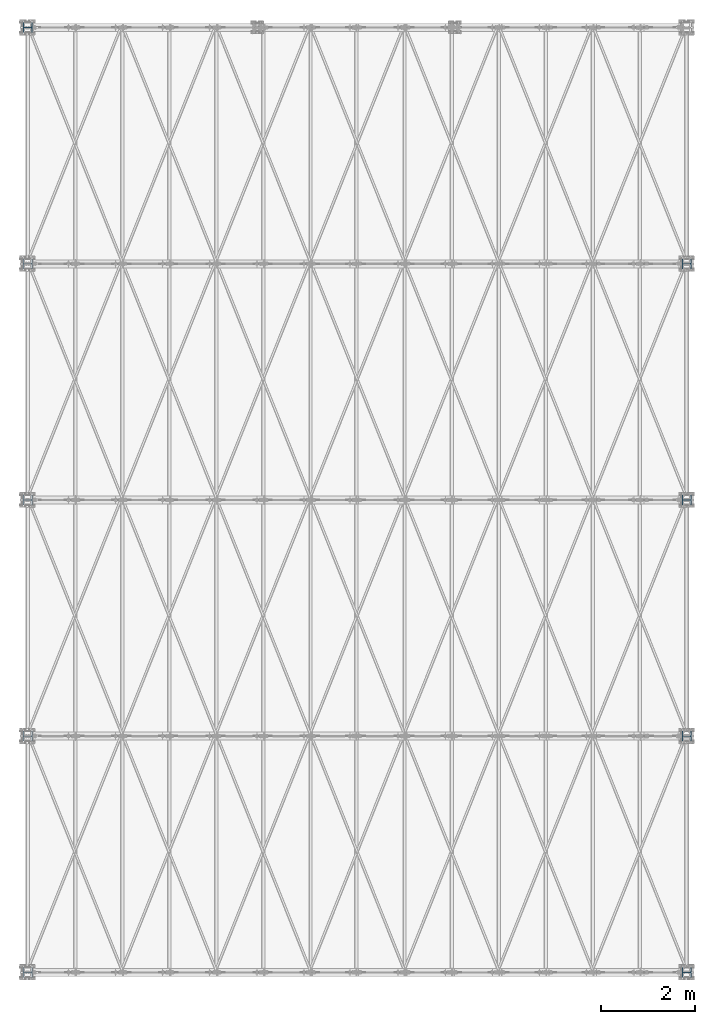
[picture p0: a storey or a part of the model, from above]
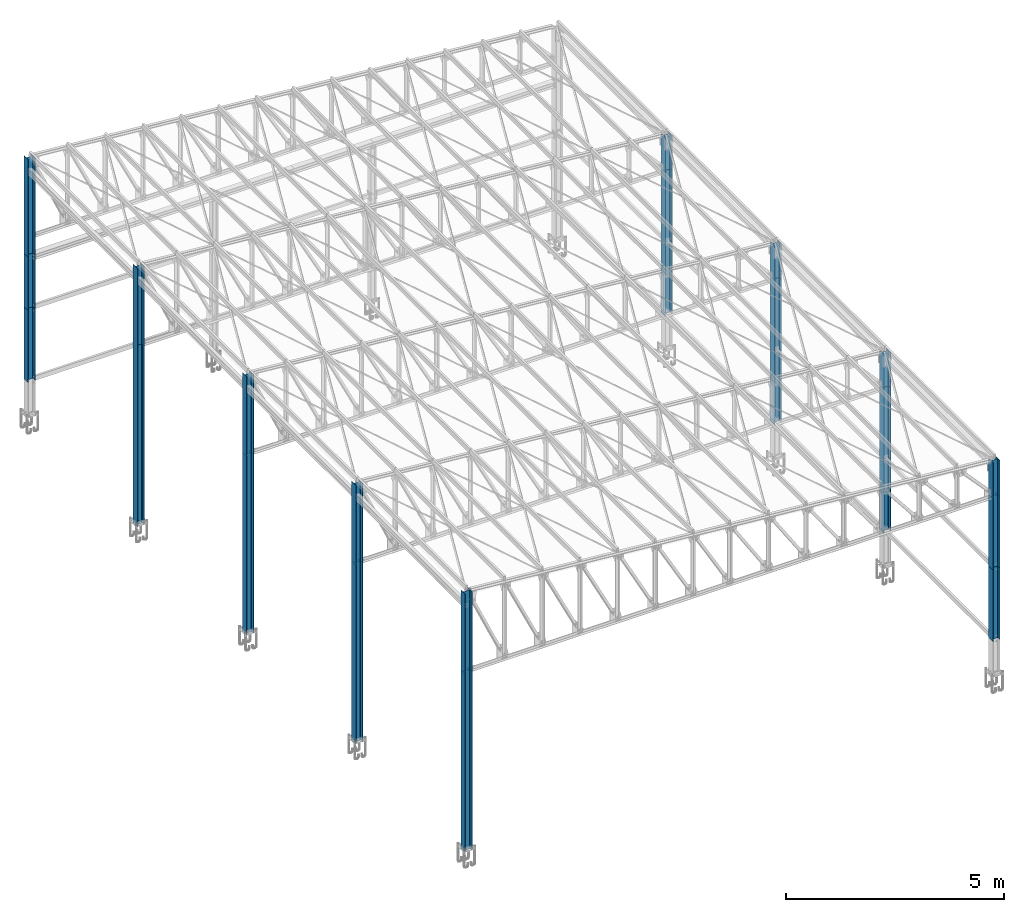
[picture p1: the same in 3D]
Properties of the parts of a building model (IFC4), part 1 of 2

# File
Description: ViewDefinition [CoordinationView]
Made in: IFC file generated by ModeSt (Tecnisoft s.a.s.)

# IfcBuildingStorey, Storey 0
In: Deposito
Elevation: 0 m

# IfcBeam: 12 HEA160 (6)
In: Storey 0
Type - PredefinedType: BEAM; Material: Acciaio
Description: 12 HEA160 - Acciaio
Pset_BeamCommon - LoadBearing: yes
BaseQuantities - ?: 0.003684 m2
Name | BaseQuantities, ? (m3) | BaseQuantities, ? (m)
70005 | 0.0103152 | 2.8
2 x 70005 | 0.0077364 | 2.1
2 x 70005 | 0.00768114 | 2.085
70005 | 0.0102415 | 2.78

# IfcBuildingElementProxy: 1 RHS120x60x8 (74)
In: Storey 0
Type - PredefinedType: MEMBER; Material: Acciaio
Description: 1 RHS120x60x8 - Acciaio
Pset_MemberCommon - LoadBearing: yes
BaseQuantities - ?: 0.002624 m2
Name | BaseQuantities, ? (m3) | BaseQuantities, ? (m)
4 x 210021 | 0.01312 | 5
4 x 230019 | 0.01312 | 5
4 x 190024 | 0.01312 | 5
4 x 170027 | 0.01312 | 5
4 x 150029 | 0.01312 | 5
4 x 130032 | 0.01312 | 5
4 x 110035 | 0.01312 | 5
4 x 90037 | 0.01312 | 5
4 x 220020 | 0.01312 | 5
4 x 200023 | 0.01312 | 5
4 x 180026 | 0.01312 | 5
4 x 160028 | 0.01312 | 5
4 x 140030 | 0.01312 | 5
4 x 120033 | 0.01312 | 5
4 x 100036 | 0.01312 | 5
4 x 280177 | 0.01312 | 5
4 x 280107 | 0.01312 | 5
280075 | 0.0128576 | 4.9
280075 | 0.0127658 | 4.865
280005 | 0.0127658 | 4.865
280005 | 0.0109814 | 4.185
280005 | 0.0128576 | 4.9
280075 | 0.0109814 | 4.185

# IfcBuildingElementProxy: 11 CONTROVENTI COPERTURA L50x5 (56)
In: Storey 0
Type - PredefinedType: MEMBER; Material: Acciaio
Description: 11 CONTROVENTI COPERTURA L50x5 - Acciaio
Pset_MemberCommon - LoadBearing: yes
BaseQuantities - ?: 0.000475 m2
Name | BaseQuantities, ? (m3) | BaseQuantities, ? (m)
4 x 210056 | 0.00255795 | 5.38516
4 x 210057 | 0.00255795 | 5.38516
250046 | 0.00255853 | 5.38638
3 x 230047 | 0.00255795 | 5.38516
3 x 230049 | 0.00255795 | 5.38516
4 x 190055 | 0.00255795 | 5.38516
4 x 190050 | 0.00255795 | 5.38516
3 x 150045 | 0.00255795 | 5.38516
4 x 170048 | 0.00255795 | 5.38516
4 x 170052 | 0.00255795 | 5.38516
2 x 130044 | 0.00255795 | 5.38516
3 x 150058 | 0.00255795 | 5.38516
110038 | 0.00255795 | 5.38516
2 x 250054 | 0.00255795 | 5.38516
250043 | 0.00255853 | 5.38638
250046 | 0.00255795 | 5.38516
230047 | 0.00255853 | 5.38638
230053 | 0.00255853 | 5.38638
2 x 130059 | 0.00255795 | 5.38516
2 x 230053 | 0.00255795 | 5.38516
250054 | 0.00255853 | 5.38638
230051 | 0.00255853 | 5.38638
110061 | 0.00255795 | 5.38516
230051 | 0.00255795 | 5.38516
230049 | 0.00255853 | 5.38638
250060 | 0.00255853 | 5.38638

# IfcBuildingElementProxy: 5 2L80x8 (330)
In: Storey 0
Type - PredefinedType: MEMBER; Material: Acciaio
Description: 5 2L80x8 - Acciaio
Pset_MemberCommon - LoadBearing: yes
BaseQuantities - ?: 0.003232 m2
Name | BaseQuantities, ? (m3) | BaseQuantities, ? (m)
4 x 230071 | 0.003232 | 1
2 x 100001 | 0.00476576 | 1.47455
2 x 13 | 0.00351369 | 1.08716
2 x 80001 | 0.0032197 | 0.996195
2 x 110001 | 0.00497708 | 1.53994
2 x 12 | 0.00379538 | 1.17431
2 x 120001 | 0.00519509 | 1.60739
2 x 11 | 0.00407706 | 1.26147
2 x 130001 | 0.00541896 | 1.67666
2 x 10 | 0.00435875 | 1.34862
2 x 140001 | 0.00564802 | 1.74753
2 x 9 | 0.00464044 | 1.43578
2 x 150001 | 0.00588165 | 1.81982
2 x 230071 | 0.00331777 | 1.02654
2 x 8 | 0.00492212 | 1.52293
2 x 160001 | 0.00616506 | 1.90751
2 x 230071 | 0.00314625 | 0.973467
2 x 7 | 0.00520381 | 1.61009
2 x 170001 | 0.00631745 | 1.95466
2 x 6 | 0.0054855 | 1.69725
2 x 180001 | 0.00660507 | 2.04365
2 x 5 | 0.00576719 | 1.7844
2 x 190001 | 0.0068524 | 2.12017
2 x 4 | 0.00604887 | 1.87156
2 x 200001 | 0.00710229 | 2.19749
2 x 3 | 0.00633056 | 1.95871
2 x 210001 | 0.00735447 | 2.27552
2 x 2 | 0.00661225 | 2.04587
2 x 230071 | 0.00324254 | 1.00326
2 x 220001 | 0.00760873 | 2.35419
2 x 1 | 0.00689394 | 2.13302
2 x 230001 | 0.0078692 | 2.43478
4 x 230072 | 0.003232 | 1
2 x 100002 | 0.00476576 | 1.47455
2 x 31 | 0.00351369 | 1.08716
2 x 80002 | 0.0032197 | 0.996195
2 x 110002 | 0.00497708 | 1.53994
2 x 30 | 0.00379538 | 1.17431
2 x 120002 | 0.00519509 | 1.60739
2 x 29 | 0.00407706 | 1.26147
2 x 130002 | 0.00541896 | 1.67666
2 x 28 | 0.00435875 | 1.34862
2 x 140002 | 0.00564802 | 1.74753
2 x 27 | 0.00464044 | 1.43578
2 x 150002 | 0.00588165 | 1.81982
2 x 230072 | 0.00331777 | 1.02654
2 x 26 | 0.00492212 | 1.52293
2 x 160002 | 0.00616506 | 1.90751
2 x 230072 | 0.00314625 | 0.973467
2 x 25 | 0.00520381 | 1.61009
2 x 170002 | 0.00631745 | 1.95466
2 x 24 | 0.0054855 | 1.69725
2 x 180002 | 0.00660507 | 2.04365
2 x 23 | 0.00576719 | 1.7844
2 x 190002 | 0.0068524 | 2.12017
2 x 22 | 0.00604887 | 1.87156
2 x 200002 | 0.00710229 | 2.19749
2 x 21 | 0.00633056 | 1.95871
2 x 210002 | 0.00735447 | 2.27552
2 x 20 | 0.00661225 | 2.04587
2 x 230072 | 0.00324254 | 1.00326
2 x 220002 | 0.00760873 | 2.35419
2 x 19 | 0.00689394 | 2.13302
2 x 230002 | 0.0078692 | 2.43478
4 x 230073 | 0.003232 | 1
2 x 100003 | 0.00476576 | 1.47455
2 x 46 | 0.00351369 | 1.08716
2 x 80003 | 0.0032197 | 0.996195
2 x 110003 | 0.00497708 | 1.53994
2 x 45 | 0.00379538 | 1.17431
2 x 120003 | 0.00519509 | 1.60739
2 x 44 | 0.00407706 | 1.26147
2 x 130003 | 0.00541896 | 1.67666
2 x 43 | 0.00435875 | 1.34862
2 x 140003 | 0.00564802 | 1.74753
2 x 42 | 0.00464044 | 1.43578
2 x 150003 | 0.00588165 | 1.81982
2 x 230073 | 0.00331777 | 1.02654
2 x 41 | 0.00492212 | 1.52293
2 x 160003 | 0.00616506 | 1.90751
2 x 230073 | 0.00314625 | 0.973467
2 x 40 | 0.00520381 | 1.61009
2 x 170003 | 0.00631745 | 1.95466
2 x 39 | 0.0054855 | 1.69725
2 x 180003 | 0.00660507 | 2.04365
2 x 38 | 0.00576719 | 1.7844
2 x 190003 | 0.0068524 | 2.12017
2 x 37 | 0.00604887 | 1.87156
2 x 200003 | 0.00710229 | 2.19749
2 x 36 | 0.00633056 | 1.95871
2 x 210003 | 0.00735447 | 2.27552
2 x 35 | 0.00661225 | 2.04587
2 x 230073 | 0.00324254 | 1.00326
2 x 220003 | 0.00760873 | 2.35419
2 x 34 | 0.00689394 | 2.13302
2 x 230003 | 0.0078692 | 2.43478
4 x 230074 | 0.003232 | 1
2 x 100004 | 0.00476576 | 1.47455
2 x 61 | 0.00351369 | 1.08716
2 x 80004 | 0.0032197 | 0.996195
2 x 110004 | 0.00497708 | 1.53994
2 x 60 | 0.00379538 | 1.17431
2 x 120004 | 0.00519509 | 1.60739
2 x 59 | 0.00407706 | 1.26147
2 x 130004 | 0.00541896 | 1.67666
2 x 58 | 0.00435875 | 1.34862
2 x 140004 | 0.00564802 | 1.74753
2 x 57 | 0.00464044 | 1.43578
2 x 150004 | 0.00588165 | 1.81982
2 x 230074 | 0.00331777 | 1.02654
2 x 56 | 0.00492212 | 1.52293
2 x 160004 | 0.00616506 | 1.90751
2 x 230074 | 0.00314625 | 0.973467
2 x 55 | 0.00520381 | 1.61009
2 x 170004 | 0.00631745 | 1.95466
2 x 54 | 0.0054855 | 1.69725
2 x 180004 | 0.00660507 | 2.04365
2 x 53 | 0.00576719 | 1.7844
2 x 190004 | 0.0068524 | 2.12017
2 x 52 | 0.00604887 | 1.87156
2 x 200004 | 0.00710229 | 2.19749
2 x 51 | 0.00633056 | 1.95871
2 x 210004 | 0.00735447 | 2.27552
2 x 50 | 0.00661225 | 2.04587
2 x 230074 | 0.00324254 | 1.00326
2 x 220004 | 0.00760873 | 2.35419
2 x 49 | 0.00689394 | 2.13302
2 x 230004 | 0.0078692 | 2.43478
4 x 230075 | 0.003232 | 1
2 x 100005 | 0.00476576 | 1.47455
2 x 78 | 0.00351369 | 1.08716
2 x 80005 | 0.0032197 | 0.996195
2 x 110005 | 0.00497708 | 1.53994
2 x 77 | 0.00379538 | 1.17431
2 x 120005 | 0.00519509 | 1.60739
2 x 76 | 0.00407706 | 1.26147
2 x 130005 | 0.00541896 | 1.67666
2 x 75 | 0.00435875 | 1.34862
2 x 140005 | 0.00564802 | 1.74753
2 x 73 | 0.00464044 | 1.43578
2 x 150005 | 0.00588165 | 1.81982
2 x 230075 | 0.00331777 | 1.02654
2 x 72 | 0.00492212 | 1.52293
2 x 160005 | 0.00616506 | 1.90751
2 x 230075 | 0.00314625 | 0.973467
2 x 71 | 0.00520381 | 1.61009
2 x 170005 | 0.00631745 | 1.95466
2 x 70 | 0.0054855 | 1.69725
2 x 180005 | 0.00660507 | 2.04365
2 x 69 | 0.00576719 | 1.7844
2 x 190005 | 0.0068524 | 2.12017
2 x 67 | 0.00604887 | 1.87156
2 x 200005 | 0.00710229 | 2.19749
2 x 66 | 0.00633056 | 1.95871
2 x 210005 | 0.00735447 | 2.27552
2 x 65 | 0.00661225 | 2.04587
2 x 230075 | 0.00324254 | 1.00326
2 x 220005 | 0.00760873 | 2.35419
2 x 64 | 0.00689394 | 2.13302
2 x 230005 | 0.0078692 | 2.43478

# IfcBuildingElementProxy: 9 ARCARECCI IPE180 (8)
In: Storey 0
Type - PredefinedType: MEMBER; Material: Acciaio
Description: 9 ARCARECCI IPE180 - Acciaio
Pset_MemberCommon - LoadBearing: yes
BaseQuantities - ?: 0.0023252 m2; ?: 0.011626 m3; ?: 5 m
Name
4 x 280019
4 x 280037

# IfcColumn: 4 PILASTRO HEA160 (6)
In: Storey 0
Type - PredefinedType: COLUMN; Material: Acciaio
Description: 4 PILASTRO HEA160 - Acciaio
Pset_ColumnCommon - LoadBearing: yes
BaseQuantities - ?: 0.003684 m2
Name | BaseQuantities, ? (m3) | BaseQuantities, ? (m)
68 | 0.003684 | 1
74 | 0.005526 | 1.5
74 | 0.007368 | 2
74 | 0.003684 | 1
68 | 0.005526 | 1.5
68 | 0.007368 | 2

# IfcColumn: 7 PILASTRO HEA200 (34)
In: Storey 0
Type - PredefinedType: COLUMN; Material: Acciaio
Description: 7 PILASTRO HEA200 - Acciaio
Pset_ColumnCommon - LoadBearing: yes
BaseQuantities - ?: 0.00502 m2
Name | BaseQuantities, ? (m3) | BaseQuantities, ? (m)
14 | 0.001004 | 0.2
16 | 0.002008 | 0.4
32 | 0.001004 | 0.2
18 | 0.002008 | 0.4
47 | 0.001004 | 0.2
33 | 0.002008 | 0.4
62 | 0.001004 | 0.2
48 | 0.002008 | 0.4
79 | 0.001004 | 0.2
63 | 0.002008 | 0.4
48 | 0.0251 | 5
18 | 0.0251 | 5
33 | 0.0251 | 5
16 | 0.0251 | 5
32 | 0.00502 | 1
14 | 0.00502 | 1
47 | 0.00502 | 1
62 | 0.00502 | 1
79 | 0.00502 | 1
2 x 32 | 0.01004 | 2
2 x 14 | 0.01004 | 2
2 x 47 | 0.01004 | 2
2 x 62 | 0.01004 | 2
79 | 0.01004 | 2
63 | 0.00502 | 1
79 | 0.00251 | 0.5
63 | 0.01004 | 2
63 | 0.00251 | 0.5
79 | 0.00753 | 1.5
63 | 0.00753 | 1.5

# IfcFastener: Collegamenti -001_-002 -002_-001 -002_-003 -003_-002 -003_-004 -004_-003 -004_-008 -008_-004 -009_-010 -010_-009 -010_-011 -011_-010 -011_-012 -012_-011 -012_-016 -016_-012 (128)
In: Storey 0
Type - PredefinedType: WELD
Description: 11x11

# IfcFastener: Collegamenti -005_-006 -008_-007 -013_-014 -016_-015 (32)
In: Storey 0
Type - PredefinedType: WELD
Description: 11x11

# IfcFastener: Collegamenti -006_-005 -006_-007 -007_-006 -007_-008 -014_-013 -014_-015 -015_-014 -015_-016 (64)
In: Storey 0
Type - PredefinedType: WELD
Description: 11x11

# IfcFastener: Collegamenti -051_7075 -053_7076 (24)
In: Storey 0
Type - PredefinedType: WELD
Description: 8x8

# IfcFastener: Collegamenti -064_-065 -065_-064 -065_-066 -066_-065 -066_-067 -067_-066 -067_-068 -068_-067 (144)
In: Storey 0
Type - PredefinedType: WELD
Name | Description
128 x Collegamenti -064_-065 -065_-064 -065_-066 -066_-065 -066_-067 -067_-066 -067_-068 -068_-067 | 7x7
16 x Collegamenti -064_-065 -065_-064 -065_-066 -066_-065 -066_-067 -067_-066 -067_-068 -068_-067 | 10x10

# IfcFastener: Collegamenti 0014_-001 0016_-054 0018_-056 0032_-002 0033_-058 0047_-003 0048_-060 0062_-004 0063_-005 0079_-008 (160)
In: Storey 0
Type - PredefinedType: WELD
Name | Description
120 x Collegamenti 0014_-001 0016_-054 0018_-056 0032_-002 0033_-058 0047_-003 0048_-060 0062_-004 0063_-005 0079_-008 | 14x14
40 x Collegamenti 0014_-001 0016_-054 0018_-056 0032_-002 0033_-058 0047_-003 0048_-060 0062_-004 0063_-005 0079_-008 | 8x8

# IfcFastener: Collegamenti 0068_-006 0074_-007 (32)
In: Storey 0
Type - PredefinedType: WELD
Name | Description
24 x Collegamenti 0068_-006 0074_-007 | 12x12
8 x Collegamenti 0068_-006 0074_-007 | 8x8

# IfcFastener: Collegamenti 7068_-014 7074_-015 (24)
In: Storey 0
Type - PredefinedType: WELD
Description: 8x8

# IfcFastener: Collegamento -069_-070 (12)
In: Storey 0
Type - PredefinedType: WELD
Description: 7x7

# IfcFastener: Collegamento -070_-069 (12)
In: Storey 0
Type - PredefinedType: WELD
Description: 7x7

# IfcFastener: Collegamento -070_-071 (12)
In: Storey 0
Type - PredefinedType: WELD
Description: 7x7

# IfcFastener: Collegamento -071_-070 (12)
In: Storey 0
Type - PredefinedType: WELD
Description: 7x7

# IfcFastener: Collegamento -071_-072 (12)
In: Storey 0
Type - PredefinedType: WELD
Description: 7x7

# IfcFastener: Collegamento -072_-071 (12)
In: Storey 0
Type - PredefinedType: WELD
Description: 7x7

# IfcFastener: Collegamento -072_-073 (12)
In: Storey 0
Type - PredefinedType: WELD
Description: 7x7

# IfcFastener: Collegamento -073_-072 (12)
In: Storey 0
Type - PredefinedType: WELD
Description: 7x7

# IfcFastener: Reticolare 2 (8)
In: Storey 0
Type - PredefinedType: WELD
Description: 10x10

# IfcFastener: Reticolare 3 (8)
In: Storey 0
Type - PredefinedType: WELD
Description: 10x10

# IfcFastener: Reticolare 4 (8)
In: Storey 0
Type - PredefinedType: WELD
Description: 10x10

# IfcFastener: Reticolare 5 (8)
In: Storey 0
Type - PredefinedType: WELD
Description: 10x10

# IfcFastener: Reticolare 6 (8)
In: Storey 0
Type - PredefinedType: WELD
Description: 10x10

# IfcMechanicalFastener: Collegamenti -001_-002 -002_-001 -002_-003 -003_-002 -003_-004 -004_-003 -004_-008 -008_-004 -009_-010 -010_-009 -010_-011 -011_-010 -011_-012 -012_-011 -012_-016 -016_-012 (256)
In: Storey 0
Type - PredefinedType: BOLT
Name | Description | NominalDiameter (m)
64 x Collegamenti -001_-002 -002_-001 -002_-003 -003_-002 -003_-004 -004_-003 -004_-008 -008_-004 -009_-010 -010_-009 -010_-011 -011_-010 -011_-012 -012_-011 -012_-016 -016_-012 | M12 | 0.0119993
64 x Collegamenti -001_-002 -002_-001 -002_-003 -003_-002 -003_-004 -004_-003 -004_-008 -008_-004 -009_-010 -010_-009 -010_-011 -011_-010 -011_-012 -012_-011 -012_-016 -016_-012 | M12 | 0.012
64 x Collegamenti -001_-002 -002_-001 -002_-003 -003_-002 -003_-004 -004_-003 -004_-008 -008_-004 -009_-010 -010_-009 -010_-011 -011_-010 -011_-012 -012_-011 -012_-016 -016_-012 | M24 | 0.024
64 x Collegamenti -001_-002 -002_-001 -002_-003 -003_-002 -003_-004 -004_-003 -004_-008 -008_-004 -009_-010 -010_-009 -010_-011 -011_-010 -011_-012 -012_-011 -012_-016 -016_-012 | M12 | 0.0119992

# IfcMechanicalFastener: Collegamenti -005_-006 -008_-007 -013_-014 -016_-015 (64)
In: Storey 0
Type - PredefinedType: BOLT
Name | Description | NominalDiameter (m)
16 x Collegamenti -005_-006 -008_-007 -013_-014 -016_-015 | M12 | 0.0119993
16 x Collegamenti -005_-006 -008_-007 -013_-014 -016_-015 | M12 | 0.012
16 x Collegamenti -005_-006 -008_-007 -013_-014 -016_-015 | M24 | 0.024
16 x Collegamenti -005_-006 -008_-007 -013_-014 -016_-015 | M12 | 0.0119992

# IfcMechanicalFastener: Collegamenti -006_-005 -006_-007 -007_-006 -007_-008 -014_-013 -014_-015 -015_-014 -015_-016 (128)
In: Storey 0
Type - PredefinedType: BOLT
Name | Description | NominalDiameter (m)
32 x Collegamenti -006_-005 -006_-007 -007_-006 -007_-008 -014_-013 -014_-015 -015_-014 -015_-016 | M12 | 0.0119993
32 x Collegamenti -006_-005 -006_-007 -007_-006 -007_-008 -014_-013 -014_-015 -015_-014 -015_-016 | M12 | 0.012
32 x Collegamenti -006_-005 -006_-007 -007_-006 -007_-008 -014_-013 -014_-015 -015_-014 -015_-016 | M24 | 0.024
32 x Collegamenti -006_-005 -006_-007 -007_-006 -007_-008 -014_-013 -014_-015 -015_-014 -015_-016 | M12 | 0.0119992

# IfcMechanicalFastener: Collegamenti -051_7075 -053_7076 (64)
In: Storey 0
Type - PredefinedType: BOLT
Name | Description | NominalDiameter (m)
16 x Collegamenti -051_7075 -053_7076 | M12 | 0.0119992
16 x Collegamenti -051_7075 -053_7076 | M12 | 0.012
16 x Collegamenti -051_7075 -053_7076 | M24 | 0.024
16 x Collegamenti -051_7075 -053_7076 | M12 | 0.0119991

# IfcMechanicalFastener: Collegamenti -064_-065 -065_-064 -065_-066 -066_-065 -066_-067 -067_-066 -067_-068 -068_-067 (128)
In: Storey 0
Type - PredefinedType: BOLT
Name | Description | NominalDiameter (m)
64 x Collegamenti -064_-065 -065_-064 -065_-066 -066_-065 -066_-067 -067_-066 -067_-068 -068_-067 | M12 | 0.0119991
32 x Collegamenti -064_-065 -065_-064 -065_-066 -066_-065 -066_-067 -067_-066 -067_-068 -068_-067 | M12 | 0.012
32 x Collegamenti -064_-065 -065_-064 -065_-066 -066_-065 -066_-067 -067_-066 -067_-068 -068_-067 | M24 | 0.024

# IfcMechanicalFastener: Collegamenti 0014_-001 0016_-054 0018_-056 0032_-002 0033_-058 0047_-003 0048_-060 0062_-004 0063_-005 0079_-008 (200)
In: Storey 0
Type - PredefinedType: BOLT
Name | Description | NominalDiameter (m)
24 x Collegamenti 0014_-001 0016_-054 0018_-056 0032_-002 0033_-058 0047_-003 0048_-060 0062_-004 0063_-005 0079_-008 | M16 | 0.016
80 x Collegamenti 0014_-001 0016_-054 0018_-056 0032_-002 0033_-058 0047_-003 0048_-060 0062_-004 0063_-005 0079_-008 | M32 | 0.032
24 x Collegamenti 0014_-001 0016_-054 0018_-056 0032_-002 0033_-058 0047_-003 0048_-060 0062_-004 0063_-005 0079_-008 | M16 | 0.0159998
48 x Collegamenti 0014_-001 0016_-054 0018_-056 0032_-002 0033_-058 0047_-003 0048_-060 0062_-004 0063_-005 0079_-008 | M16 | 0.0160001
24 x Collegamenti 0014_-001 0016_-054 0018_-056 0032_-002 0033_-058 0047_-003 0048_-060 0062_-004 0063_-005 0079_-008 | M16 | 0.0159988

# IfcMechanicalFastener: Collegamenti 0068_-006 0074_-007 (40)
In: Storey 0
Type - PredefinedType: BOLT
Name | Description | NominalDiameter (m)
24 x Collegamenti 0068_-006 0074_-007 | M12 | 0.0119992
16 x Collegamenti 0068_-006 0074_-007 | M24 | 0.024

# IfcMechanicalFastener: Collegamenti 7068_-014 7074_-015 (32)
In: Storey 0
Type - PredefinedType: BOLT
Name | Description | NominalDiameter (m)
16 x Collegamenti 7068_-014 7074_-015 | M12 | 0.0119991
8 x Collegamenti 7068_-014 7074_-015 | M12 | 0.012
8 x Collegamenti 7068_-014 7074_-015 | M24 | 0.024

# IfcMechanicalFastener: Collegamento -069_-070 (16)
In: Storey 0
Type - PredefinedType: BOLT
Name | Description | NominalDiameter (m)
8 x Collegamento -069_-070 | M12 | 0.0119999
4 x Collegamento -069_-070 | M12 | 0.012
4 x Collegamento -069_-070 | M24 | 0.024

# IfcMechanicalFastener: Collegamento -070_-069 (16)
In: Storey 0
Type - PredefinedType: BOLT
Name | Description | NominalDiameter (m)
8 x Collegamento -070_-069 | M12 | 0.0119999
4 x Collegamento -070_-069 | M12 | 0.012
4 x Collegamento -070_-069 | M24 | 0.024

# IfcMechanicalFastener: Collegamento -070_-071 (16)
In: Storey 0
Type - PredefinedType: BOLT
Name | Description | NominalDiameter (m)
8 x Collegamento -070_-071 | M12 | 0.0119999
4 x Collegamento -070_-071 | M12 | 0.012
4 x Collegamento -070_-071 | M24 | 0.024

# IfcMechanicalFastener: Collegamento -071_-070 (16)
In: Storey 0
Type - PredefinedType: BOLT
Name | Description | NominalDiameter (m)
8 x Collegamento -071_-070 | M12 | 0.0119999
4 x Collegamento -071_-070 | M12 | 0.012
4 x Collegamento -071_-070 | M24 | 0.024

# IfcMechanicalFastener: Collegamento -071_-072 (16)
In: Storey 0
Type - PredefinedType: BOLT
Name | Description | NominalDiameter (m)
8 x Collegamento -071_-072 | M12 | 0.0119999
4 x Collegamento -071_-072 | M12 | 0.012
4 x Collegamento -071_-072 | M24 | 0.024

# IfcMechanicalFastener: Collegamento -072_-071 (16)
In: Storey 0
Type - PredefinedType: BOLT
Name | Description | NominalDiameter (m)
8 x Collegamento -072_-071 | M12 | 0.0119999
4 x Collegamento -072_-071 | M12 | 0.012
4 x Collegamento -072_-071 | M24 | 0.024

# IfcMechanicalFastener: Collegamento -072_-073 (16)
In: Storey 0
Type - PredefinedType: BOLT
Name | Description | NominalDiameter (m)
8 x Collegamento -072_-073 | M12 | 0.0119999
4 x Collegamento -072_-073 | M12 | 0.012
4 x Collegamento -072_-073 | M24 | 0.024

# IfcMechanicalFastener: Collegamento -073_-072 (16)
In: Storey 0
Type - PredefinedType: BOLT
Name | Description | NominalDiameter (m)
8 x Collegamento -073_-072 | M12 | 0.0119999
4 x Collegamento -073_-072 | M12 | 0.012
4 x Collegamento -073_-072 | M24 | 0.024

# IfcMechanicalFastener: Reticolare 2 (880)
In: Storey 0
Type - PredefinedType: BOLT
Name | Description | NominalDiameter (m)
12 x Reticolare 2 | M12 | 0.0119991
172 x Reticolare 2 | M12 | 0.012
156 x Reticolare 2 | M24 | 0.024
8 x Reticolare 2 | M16 | 0.0159985
20 x Reticolare 2 | M16 | 0.016
20 x Reticolare 2 | M32 | 0.032
84 x Reticolare 2 | M12 | 0.0119999
50 x Reticolare 2 | M14 | 0.0139997
44 x Reticolare 2 | M14 | 0.014
44 x Reticolare 2 | M28 | 0.028
12 x Reticolare 2 | M14 | 0.0139998
42 x Reticolare 2 | M12 | 0.0119997
4 x Reticolare 2 | M14 | 0.0139994
4 x Reticolare 2 | M14 | 0.0139995
60 x Reticolare 2 | M12 | 0.0119996
16 x Reticolare 2 | M12 | 0.0119994
26 x Reticolare 2 | M16 | 0.0159997
4 x Reticolare 2 | M12 | 0.0119993
2 x Reticolare 2 | M12 | 0.0119998
2 x Reticolare 2 | M16 | 0.0159998
4 x Reticolare 2 | M16 | 0.0159988
24 x Reticolare 2 | M12 | 0.0120001
12 x Reticolare 2 | M12 | 0.0119989
10 x Reticolare 2 | M14 | 0.0139996
4 x Reticolare 2 | M14 | 0.013999
34 x Reticolare 2 | M12 | 0.011999
6 x Reticolare 2 | M12 | 0.0119995
4 x Reticolare 2 | M14 | 0.0140001

# IfcMechanicalFastener: Reticolare 3 (880)
In: Storey 0
Type - PredefinedType: BOLT
Name | Description | NominalDiameter (m)
52 x Reticolare 3 | M14 | 0.0139997
42 x Reticolare 3 | M14 | 0.014
42 x Reticolare 3 | M28 | 0.028
6 x Reticolare 3 | M18 | 0.0179991
4 x Reticolare 3 | M18 | 0.018
4 x Reticolare 3 | M36 | 0.036
76 x Reticolare 3 | M12 | 0.0119999
162 x Reticolare 3 | M12 | 0.012
146 x Reticolare 3 | M24 | 0.024
40 x Reticolare 3 | M16 | 0.016
28 x Reticolare 3 | M32 | 0.032
4 x Reticolare 3 | M16 | 0.0159996
40 x Reticolare 3 | M12 | 0.0119997
8 x Reticolare 3 | M14 | 0.0139998
4 x Reticolare 3 | M14 | 0.0139994
62 x Reticolare 3 | M12 | 0.0119996
16 x Reticolare 3 | M12 | 0.0119994
26 x Reticolare 3 | M16 | 0.0159997
4 x Reticolare 3 | M12 | 0.0119993
2 x Reticolare 3 | M12 | 0.0119998
2 x Reticolare 3 | M16 | 0.0159998
12 x Reticolare 3 | M16 | 0.0159988
16 x Reticolare 3 | M12 | 0.0120001
12 x Reticolare 3 | M12 | 0.0119989
8 x Reticolare 3 | M12 | 0.0119991
8 x Reticolare 3 | M14 | 0.0139989
4 x Reticolare 3 | M14 | 0.0139996
4 x Reticolare 3 | M14 | 0.013999
34 x Reticolare 3 | M12 | 0.011999
2 x Reticolare 3 | M18 | 0.017999
6 x Reticolare 3 | M12 | 0.0119995
4 x Reticolare 3 | M14 | 0.0140001

# IfcMechanicalFastener: Reticolare 4 (880)
In: Storey 0
Type - PredefinedType: BOLT
Name | Description | NominalDiameter (m)
44 x Reticolare 4 | M14 | 0.0139997
36 x Reticolare 4 | M14 | 0.014
36 x Reticolare 4 | M28 | 0.028
8 x Reticolare 4 | M16 | 0.0159985
40 x Reticolare 4 | M16 | 0.016
28 x Reticolare 4 | M32 | 0.032
84 x Reticolare 4 | M12 | 0.0119999
172 x Reticolare 4 | M12 | 0.012
156 x Reticolare 4 | M24 | 0.024
4 x Reticolare 4 | M16 | 0.0159996
48 x Reticolare 4 | M12 | 0.0119997
8 x Reticolare 4 | M14 | 0.0139998
4 x Reticolare 4 | M14 | 0.0139994
62 x Reticolare 4 | M12 | 0.0119996
16 x Reticolare 4 | M12 | 0.0119994
4 x Reticolare 4 | M12 | 0.0119993
18 x Reticolare 4 | M16 | 0.0159997
2 x Reticolare 4 | M12 | 0.0119998
2 x Reticolare 4 | M16 | 0.0159998
12 x Reticolare 4 | M16 | 0.0159988
20 x Reticolare 4 | M12 | 0.0120001
12 x Reticolare 4 | M12 | 0.0119989
8 x Reticolare 4 | M12 | 0.0119991
4 x Reticolare 4 | M14 | 0.0139996
4 x Reticolare 4 | M14 | 0.013999
34 x Reticolare 4 | M12 | 0.011999
4 x Reticolare 4 | M14 | 0.0139989
6 x Reticolare 4 | M12 | 0.0119995
4 x Reticolare 4 | M14 | 0.0140001

# IfcMechanicalFastener: Reticolare 5 (880)
In: Storey 0
Type - PredefinedType: BOLT
Name | Description | NominalDiameter (m)
84 x Reticolare 5 | M14 | 0.0139997
54 x Reticolare 5 | M14 | 0.014
54 x Reticolare 5 | M28 | 0.028
8 x Reticolare 5 | M16 | 0.0159985
12 x Reticolare 5 | M16 | 0.016
8 x Reticolare 5 | M32 | 0.032
84 x Reticolare 5 | M12 | 0.0119999
174 x Reticolare 5 | M12 | 0.012
158 x Reticolare 5 | M24 | 0.024
4 x Reticolare 5 | M16 | 0.0159996
48 x Reticolare 5 | M12 | 0.0119997
8 x Reticolare 5 | M14 | 0.0139998
4 x Reticolare 5 | M14 | 0.0139994
62 x Reticolare 5 | M12 | 0.0119996
16 x Reticolare 5 | M12 | 0.0119994
4 x Reticolare 5 | M12 | 0.0119993
2 x Reticolare 5 | M12 | 0.0119998
24 x Reticolare 5 | M12 | 0.0120001
12 x Reticolare 5 | M12 | 0.0119989
8 x Reticolare 5 | M12 | 0.0119991
4 x Reticolare 5 | M14 | 0.0139996
4 x Reticolare 5 | M14 | 0.013999
34 x Reticolare 5 | M12 | 0.011999
6 x Reticolare 5 | M12 | 0.0119995
4 x Reticolare 5 | M14 | 0.0140001

# IfcMechanicalFastener: Reticolare 6 (880)
In: Storey 0
Type - PredefinedType: BOLT
Name | Description | NominalDiameter (m)
28 x Reticolare 6 | M12 | 0.0119991
184 x Reticolare 6 | M12 | 0.012
168 x Reticolare 6 | M24 | 0.024
8 x Reticolare 6 | M16 | 0.0159985
4 x Reticolare 6 | M16 | 0.016
4 x Reticolare 6 | M32 | 0.032
84 x Reticolare 6 | M12 | 0.0119999
58 x Reticolare 6 | M14 | 0.0139997
48 x Reticolare 6 | M14 | 0.014
48 x Reticolare 6 | M28 | 0.028
12 x Reticolare 6 | M14 | 0.0139998
50 x Reticolare 6 | M12 | 0.0119997
4 x Reticolare 6 | M14 | 0.0139994
4 x Reticolare 6 | M14 | 0.0139995
60 x Reticolare 6 | M12 | 0.0119996
16 x Reticolare 6 | M12 | 0.0119994
4 x Reticolare 6 | M12 | 0.0119993
2 x Reticolare 6 | M12 | 0.0119998
24 x Reticolare 6 | M12 | 0.0120001
12 x Reticolare 6 | M12 | 0.0119989
10 x Reticolare 6 | M14 | 0.0139996
4 x Reticolare 6 | M14 | 0.013999
34 x Reticolare 6 | M12 | 0.011999
6 x Reticolare 6 | M12 | 0.0119995
4 x Reticolare 6 | M14 | 0.0140001

# IfcPlate: Collegamenti -001_-002 -002_-001 -002_-003 -003_-002 -003_-004 -004_-003 -004_-008 -008_-004 -009_-010 -010_-009 -010_-011 -011_-010 -011_-012 -012_-011 -012_-016 -016_-012 (16)
In: Storey 0
Type - PredefinedType: SHEET

# IfcPlate: Collegamenti -005_-006 -008_-007 -013_-014 -016_-015 (4)
In: Storey 0
Type - PredefinedType: SHEET

# IfcPlate: Collegamenti -006_-005 -006_-007 -007_-006 -007_-008 -014_-013 -014_-015 -015_-014 -015_-016 (8)
In: Storey 0
Type - PredefinedType: SHEET

# IfcPlate: Collegamenti -051_7075 -053_7076 (2)
In: Storey 0
Type - PredefinedType: SHEET

# IfcPlate: Collegamenti -064_-065 -065_-064 -065_-066 -066_-065 -066_-067 -067_-066 -067_-068 -068_-067 (32)
In: Storey 0
Type - PredefinedType: SHEET

# IfcPlate: Collegamenti 0014_-001 0016_-054 0018_-056 0032_-002 0033_-058 0047_-003 0048_-060 0062_-004 0063_-005 0079_-008 (90)
In: Storey 0
Type - PredefinedType: SHEET

# IfcPlate: Collegamenti 0068_-006 0074_-007 (18)
In: Storey 0
Type - PredefinedType: SHEET

# IfcPlate: Collegamenti 7068_-014 7074_-015 (2)
In: Storey 0
Type - PredefinedType: SHEET

# IfcPlate: Collegamento -069_-070
In: Storey 0
Type - PredefinedType: SHEET

# IfcPlate: Collegamento -070_-069
In: Storey 0
Type - PredefinedType: SHEET

# IfcPlate: Collegamento -070_-071
In: Storey 0
Type - PredefinedType: SHEET

# IfcPlate: Collegamento -071_-070
In: Storey 0
Type - PredefinedType: SHEET

# IfcPlate: Collegamento -071_-072
In: Storey 0
Type - PredefinedType: SHEET

# IfcPlate: Collegamento -072_-071
In: Storey 0
Type - PredefinedType: SHEET

# IfcPlate: Collegamento -072_-073
In: Storey 0
Type - PredefinedType: SHEET

# IfcPlate: Collegamento -073_-072
In: Storey 0
Type - PredefinedType: SHEET

# IfcPlate: Reticolare 2 (30)
In: Storey 0
Type - PredefinedType: SHEET

# IfcPlate: Reticolare 3 (30)
In: Storey 0
Type - PredefinedType: SHEET

# IfcPlate: Reticolare 4 (30)
In: Storey 0
Type - PredefinedType: SHEET

# IfcPlate: Reticolare 5 (30)
In: Storey 0
Type - PredefinedType: SHEET

# IfcPlate: Reticolare 6 (30)
In: Storey 0
Type - PredefinedType: SHEET

# IfcReinforcingBar (6)
In: Storey 0
Name | NominalDiameter (m) | CrossSectionArea (m2) | BarLength (m)
 | 0.016 | 0.00020106 | 0.469
 | 0.016 | 0.00020106 | 0.0187288
 | 0.016 | 0.00020106 | 0.0479995
 | 0.012 | 0.0001131 | 0.478
 | 0.012 | 0.0001131 | 0.0140467
 | 0.012 | 0.0001131 | 0.0359994

# IfcSlab: 1 Solaio copertura (56)
In: Storey 0
Type - PredefinedType: FLOOR; Material: Concrete
Description: 1 Solaio copertura - Altezza solaio 0.100000 - Spessore cappa 0.000000 -
Pset_SlabCommon - LoadBearing: yes
BaseQuantities - ?: 0.1 m
Name | BaseQuantities, ? (m2) | BaseQuantities, ? (m3)
1700 | -4.84779 | -0.484779
1800 | -4.98097 | -0.498097
1900 | -4.98097 | -0.498097
2000 | -4.98097 | -0.498097
2100 | -4.98097 | -0.498097
2200 | -4.98097 | -0.498097
2300 | -4.99734 | -0.499734
2301 | -4.99734 | -0.499734
2201 | -4.98097 | -0.498097
2101 | -4.98097 | -0.498097
2001 | -4.98097 | -0.498097
1901 | -4.98097 | -0.498097
1801 | -4.98097 | -0.498097
1701 | -4.84779 | -0.484779
1600 | -5.11416 | -0.511416
1500 | -4.98097 | -0.498097
1400 | -4.98097 | -0.498097
1300 | -4.98097 | -0.498097
1200 | -4.98097 | -0.498097
1100 | -4.98097 | -0.498097
1000 | -4.98097 | -0.498097
1001 | -4.98097 | -0.498097
1101 | -4.98097 | -0.498097
1201 | -4.98097 | -0.498097
1301 | -4.98097 | -0.498097
1401 | -4.98097 | -0.498097
1501 | -4.98097 | -0.498097
1601 | -5.11416 | -0.511416
1702 | -4.84779 | -0.484779
1802 | -4.98097 | -0.498097
1902 | -4.98097 | -0.498097
2002 | -4.98097 | -0.498097
2102 | -4.98097 | -0.498097
2202 | -4.98097 | -0.498097
2302 | -4.99734 | -0.499734
1602 | -5.11416 | -0.511416
1502 | -4.98097 | -0.498097
1402 | -4.98097 | -0.498097
1302 | -4.98097 | -0.498097
1202 | -4.98097 | -0.498097
1102 | -4.98097 | -0.498097
1002 | -4.98097 | -0.498097
2303 | -4.99734 | -0.499734
2203 | -4.98097 | -0.498097
2103 | -4.98097 | -0.498097
1903 | -4.98097 | -0.498097
1803 | -4.98097 | -0.498097
1703 | -4.84779 | -0.484779
1603 | -5.11416 | -0.511416
1503 | -4.98097 | -0.498097
1403 | -4.98097 | -0.498097
1203 | -4.98097 | -0.498097
1103 | -4.98097 | -0.498097
1003 | -4.98097 | -0.498097
1303 | -4.98097 | -0.498097
2003 | -4.98097 | -0.498097

# IfcReinforcingBarType, no part of this type: type
PredefinedType: MAIN; NominalDiameter: 0.016 m; CrossSectionArea: 0.00020106 m2; BarLength: 0.469 m; Material: Steel

# IfcReinforcingBarType, no part of this type: type
PredefinedType: MAIN; NominalDiameter: 0.016 m; CrossSectionArea: 0.00020106 m2; BarLength: 0.0187288 m; Material: Steel

# IfcReinforcingBarType, no part of this type: type
PredefinedType: MAIN; NominalDiameter: 0.016 m; CrossSectionArea: 0.00020106 m2; BarLength: 0.0479995 m; Material: Steel

# IfcReinforcingBarType, no part of this type: type
PredefinedType: MAIN; NominalDiameter: 0.012 m; CrossSectionArea: 0.0001131 m2; BarLength: 0.478 m; Material: Steel

# IfcReinforcingBarType, no part of this type: type
PredefinedType: MAIN; NominalDiameter: 0.012 m; CrossSectionArea: 0.0001131 m2; BarLength: 0.0140467 m; Material: Steel

# IfcReinforcingBarType, no part of this type: type
PredefinedType: MAIN; NominalDiameter: 0.012 m; CrossSectionArea: 0.0001131 m2; BarLength: 0.0359994 m; Material: Steel

# Material: Acciaio
Acciaio - Mass Density: 7850; Poisson Ratio: 0.3; Shear Modulus: 8000000000; Thermal Expansion Coefficient: 0.00001; Young Modulus: 20999999488

# Material: Acciaio
Acciaio - Mass Density: 7850; Poisson Ratio: 0.3; Shear Modulus: 8000000000; Thermal Expansion Coefficient: 0.00001; Young Modulus: 20999999488

# Material: Acciaio
Acciaio - Mass Density: 7850; Poisson Ratio: 0.3; Shear Modulus: 8000000000; Thermal Expansion Coefficient: 0.00001; Young Modulus: 20999999488

# Material: Acciaio
Acciaio - Mass Density: 7850; Poisson Ratio: 0.3; Shear Modulus: 8000000000; Thermal Expansion Coefficient: 0.00001; Young Modulus: 20999999488

# Material: Acciaio
Acciaio - Mass Density: 7850; Poisson Ratio: 0.3; Shear Modulus: 8000000000; Thermal Expansion Coefficient: 0.00001; Young Modulus: 20999999488

# Material: Acciaio
Acciaio - Mass Density: 7850; Poisson Ratio: 0.3; Shear Modulus: 8000000000; Thermal Expansion Coefficient: 0.00001; Young Modulus: 20999999488

# Material: Acciaio
Acciaio - Mass Density: 7850; Poisson Ratio: 0.3; Shear Modulus: 8000000000; Thermal Expansion Coefficient: 0.00001; Young Modulus: 20999999488

# Material: Acciaio
Acciaio - Mass Density: 7850; Poisson Ratio: 0.3; Shear Modulus: 8000000000; Thermal Expansion Coefficient: 0.00001; Young Modulus: 20999999488

# Material: Acciaio
Acciaio - Mass Density: 7850; Poisson Ratio: 0.3; Shear Modulus: 8000000000; Thermal Expansion Coefficient: 0.00001; Young Modulus: 20999999488

# Material: Acciaio
Acciaio - Mass Density: 7850; Poisson Ratio: 0.3; Shear Modulus: 8000000000; Thermal Expansion Coefficient: 0.00001; Young Modulus: 20999999488

# Material: Acciaio
Acciaio - Mass Density: 7850; Poisson Ratio: 0.3; Shear Modulus: 8000000000; Thermal Expansion Coefficient: 0.00001; Young Modulus: 20999999488

# Material: Acciaio
Acciaio - Mass Density: 7850; Poisson Ratio: 0.3; Shear Modulus: 8000000000; Thermal Expansion Coefficient: 0.00001; Young Modulus: 20999999488

# Material: Acciaio
Acciaio - Mass Density: 7850; Poisson Ratio: 0.3; Shear Modulus: 8000000000; Thermal Expansion Coefficient: 0.00001; Young Modulus: 20999999488

# Material: Acciaio
Acciaio - Mass Density: 7850; Poisson Ratio: 0.3; Shear Modulus: 8000000000; Thermal Expansion Coefficient: 0.00001; Young Modulus: 20999999488

# Material: Acciaio
Acciaio - Mass Density: 7850; Poisson Ratio: 0.3; Shear Modulus: 8000000000; Thermal Expansion Coefficient: 0.00001; Young Modulus: 20999999488

# Material: Acciaio
Acciaio - Mass Density: 7850; Poisson Ratio: 0.3; Shear Modulus: 8000000000; Thermal Expansion Coefficient: 0.00001; Young Modulus: 20999999488

# Material: Acciaio
Acciaio - Mass Density: 7850; Poisson Ratio: 0.3; Shear Modulus: 8000000000; Thermal Expansion Coefficient: 0.00001; Young Modulus: 20999999488

# Material: Acciaio
Acciaio - Mass Density: 7850; Poisson Ratio: 0.3; Shear Modulus: 8000000000; Thermal Expansion Coefficient: 0.00001; Young Modulus: 20999999488

# Material: Acciaio
Acciaio - Mass Density: 7850; Poisson Ratio: 0.3; Shear Modulus: 8000000000; Thermal Expansion Coefficient: 0.00001; Young Modulus: 20999999488

# Material: Acciaio
Acciaio - Mass Density: 7850; Poisson Ratio: 0.3; Shear Modulus: 8000000000; Thermal Expansion Coefficient: 0.00001; Young Modulus: 20999999488

# Material: Acciaio
Acciaio - Mass Density: 7850; Poisson Ratio: 0.3; Shear Modulus: 8000000000; Thermal Expansion Coefficient: 0.00001; Young Modulus: 20999999488

# Material: Acciaio
Acciaio - Mass Density: 7850; Poisson Ratio: 0.3; Shear Modulus: 8000000000; Thermal Expansion Coefficient: 0.00001; Young Modulus: 20999999488

# Material: Acciaio
Acciaio - Mass Density: 7850; Poisson Ratio: 0.3; Shear Modulus: 8000000000; Thermal Expansion Coefficient: 0.00001; Young Modulus: 20999999488

# Material: Acciaio
Acciaio - Mass Density: 7850; Poisson Ratio: 0.3; Shear Modulus: 8000000000; Thermal Expansion Coefficient: 0.00001; Young Modulus: 20999999488

# Material: Acciaio
Acciaio - Mass Density: 7850; Poisson Ratio: 0.3; Shear Modulus: 8000000000; Thermal Expansion Coefficient: 0.00001; Young Modulus: 20999999488

# Material: Acciaio
Acciaio - Mass Density: 7850; Poisson Ratio: 0.3; Shear Modulus: 8000000000; Thermal Expansion Coefficient: 0.00001; Young Modulus: 20999999488

# Material: Acciaio
Acciaio - Mass Density: 7850; Poisson Ratio: 0.3; Shear Modulus: 8000000000; Thermal Expansion Coefficient: 0.00001; Young Modulus: 20999999488

# Material: Acciaio
Acciaio - Mass Density: 7850; Poisson Ratio: 0.3; Shear Modulus: 8000000000; Thermal Expansion Coefficient: 0.00001; Young Modulus: 20999999488

# Material: Acciaio
Acciaio - Mass Density: 7850; Poisson Ratio: 0.3; Shear Modulus: 8000000000; Thermal Expansion Coefficient: 0.00001; Young Modulus: 20999999488

# Material: Acciaio
Acciaio - Mass Density: 7850; Poisson Ratio: 0.3; Shear Modulus: 8000000000; Thermal Expansion Coefficient: 0.00001; Young Modulus: 20999999488

# Material: Acciaio
Acciaio - Mass Density: 7850; Poisson Ratio: 0.3; Shear Modulus: 8000000000; Thermal Expansion Coefficient: 0.00001; Young Modulus: 20999999488

# Material: Acciaio
Acciaio - Mass Density: 7850; Poisson Ratio: 0.3; Shear Modulus: 8000000000; Thermal Expansion Coefficient: 0.00001; Young Modulus: 20999999488

# Material: Acciaio
Acciaio - Mass Density: 7850; Poisson Ratio: 0.3; Shear Modulus: 8000000000; Thermal Expansion Coefficient: 0.00001; Young Modulus: 20999999488

# Material: Acciaio
Acciaio - Mass Density: 7850; Poisson Ratio: 0.3; Shear Modulus: 8000000000; Thermal Expansion Coefficient: 0.00001; Young Modulus: 20999999488

# Material: Acciaio
Acciaio - Mass Density: 7850; Poisson Ratio: 0.3; Shear Modulus: 8000000000; Thermal Expansion Coefficient: 0.00001; Young Modulus: 20999999488

# Material: Acciaio
Acciaio - Mass Density: 7850; Poisson Ratio: 0.3; Shear Modulus: 8000000000; Thermal Expansion Coefficient: 0.00001; Young Modulus: 20999999488

# Material: Acciaio
Acciaio - Mass Density: 7850; Poisson Ratio: 0.3; Shear Modulus: 8000000000; Thermal Expansion Coefficient: 0.00001; Young Modulus: 20999999488

# Material: Acciaio
Acciaio - Mass Density: 7850; Poisson Ratio: 0.3; Shear Modulus: 8000000000; Thermal Expansion Coefficient: 0.00001; Young Modulus: 20999999488

# Material: Acciaio
Acciaio - Mass Density: 7850; Poisson Ratio: 0.3; Shear Modulus: 8000000000; Thermal Expansion Coefficient: 0.00001; Young Modulus: 20999999488

# Material: Acciaio
Acciaio - Mass Density: 7850; Poisson Ratio: 0.3; Shear Modulus: 8000000000; Thermal Expansion Coefficient: 0.00001; Young Modulus: 20999999488

# Material: Acciaio
Acciaio - Mass Density: 7850; Poisson Ratio: 0.3; Shear Modulus: 8000000000; Thermal Expansion Coefficient: 0.00001; Young Modulus: 20999999488

# Material: Acciaio
Acciaio - Mass Density: 7850; Poisson Ratio: 0.3; Shear Modulus: 8000000000; Thermal Expansion Coefficient: 0.00001; Young Modulus: 20999999488

# Material: Acciaio
Acciaio - Mass Density: 7850; Poisson Ratio: 0.3; Shear Modulus: 8000000000; Thermal Expansion Coefficient: 0.00001; Young Modulus: 20999999488

# Material: Acciaio
Acciaio - Mass Density: 7850; Poisson Ratio: 0.3; Shear Modulus: 8000000000; Thermal Expansion Coefficient: 0.00001; Young Modulus: 20999999488

# Material: Acciaio
Acciaio - Mass Density: 7850; Poisson Ratio: 0.3; Shear Modulus: 8000000000; Thermal Expansion Coefficient: 0.00001; Young Modulus: 20999999488

# Material: Acciaio
Acciaio - Mass Density: 7850; Poisson Ratio: 0.3; Shear Modulus: 8000000000; Thermal Expansion Coefficient: 0.00001; Young Modulus: 20999999488

# Material: Acciaio
Acciaio - Mass Density: 7850; Poisson Ratio: 0.3; Shear Modulus: 8000000000; Thermal Expansion Coefficient: 0.00001; Young Modulus: 20999999488

# Material: Acciaio
Acciaio - Mass Density: 7850; Poisson Ratio: 0.3; Shear Modulus: 8000000000; Thermal Expansion Coefficient: 0.00001; Young Modulus: 20999999488

# Material: Acciaio
Acciaio - Mass Density: 7850; Poisson Ratio: 0.3; Shear Modulus: 8000000000; Thermal Expansion Coefficient: 0.00001; Young Modulus: 20999999488

# Material: Acciaio
Acciaio - Mass Density: 7850; Poisson Ratio: 0.3; Shear Modulus: 8000000000; Thermal Expansion Coefficient: 0.00001; Young Modulus: 20999999488

# Material: Acciaio
Acciaio - Mass Density: 7850; Poisson Ratio: 0.3; Shear Modulus: 8000000000; Thermal Expansion Coefficient: 0.00001; Young Modulus: 20999999488

# Material: Acciaio
Acciaio - Mass Density: 7850; Poisson Ratio: 0.3; Shear Modulus: 8000000000; Thermal Expansion Coefficient: 0.00001; Young Modulus: 20999999488

# Material: Acciaio
Acciaio - Mass Density: 7850; Poisson Ratio: 0.3; Shear Modulus: 8000000000; Thermal Expansion Coefficient: 0.00001; Young Modulus: 20999999488

# Material: Acciaio
Acciaio - Mass Density: 7850; Poisson Ratio: 0.3; Shear Modulus: 8000000000; Thermal Expansion Coefficient: 0.00001; Young Modulus: 20999999488

# Material: Acciaio
Acciaio - Mass Density: 7850; Poisson Ratio: 0.3; Shear Modulus: 8000000000; Thermal Expansion Coefficient: 0.00001; Young Modulus: 20999999488

# Material: Acciaio
Acciaio - Mass Density: 7850; Poisson Ratio: 0.3; Shear Modulus: 8000000000; Thermal Expansion Coefficient: 0.00001; Young Modulus: 20999999488

# Material: Acciaio
Acciaio - Mass Density: 7850; Poisson Ratio: 0.3; Shear Modulus: 8000000000; Thermal Expansion Coefficient: 0.00001; Young Modulus: 20999999488

# Material: Acciaio
Acciaio - Mass Density: 7850; Poisson Ratio: 0.3; Shear Modulus: 8000000000; Thermal Expansion Coefficient: 0.00001; Young Modulus: 20999999488

# Material: Acciaio
Acciaio - Mass Density: 7850; Poisson Ratio: 0.3; Shear Modulus: 8000000000; Thermal Expansion Coefficient: 0.00001; Young Modulus: 20999999488

# Material: Acciaio
Acciaio - Mass Density: 7850; Poisson Ratio: 0.3; Shear Modulus: 8000000000; Thermal Expansion Coefficient: 0.00001; Young Modulus: 20999999488

# Material: Acciaio
Acciaio - Mass Density: 7850; Poisson Ratio: 0.3; Shear Modulus: 8000000000; Thermal Expansion Coefficient: 0.00001; Young Modulus: 20999999488

# Material: Acciaio
Acciaio - Mass Density: 7850; Poisson Ratio: 0.3; Shear Modulus: 8000000000; Thermal Expansion Coefficient: 0.00001; Young Modulus: 20999999488

# Material: Acciaio
Acciaio - Mass Density: 7850; Poisson Ratio: 0.3; Shear Modulus: 8000000000; Thermal Expansion Coefficient: 0.00001; Young Modulus: 20999999488

# Material: Acciaio
Acciaio - Mass Density: 7850; Poisson Ratio: 0.3; Shear Modulus: 8000000000; Thermal Expansion Coefficient: 0.00001; Young Modulus: 20999999488

# Material: Acciaio
Acciaio - Mass Density: 7850; Poisson Ratio: 0.3; Shear Modulus: 8000000000; Thermal Expansion Coefficient: 0.00001; Young Modulus: 20999999488

# Material: Acciaio
Acciaio - Mass Density: 7850; Poisson Ratio: 0.3; Shear Modulus: 8000000000; Thermal Expansion Coefficient: 0.00001; Young Modulus: 20999999488

# Material: Acciaio
Acciaio - Mass Density: 7850; Poisson Ratio: 0.3; Shear Modulus: 8000000000; Thermal Expansion Coefficient: 0.00001; Young Modulus: 20999999488

# Material: Acciaio
Acciaio - Mass Density: 7850; Poisson Ratio: 0.3; Shear Modulus: 8000000000; Thermal Expansion Coefficient: 0.00001; Young Modulus: 20999999488

# Material: Acciaio
Acciaio - Mass Density: 7850; Poisson Ratio: 0.3; Shear Modulus: 8000000000; Thermal Expansion Coefficient: 0.00001; Young Modulus: 20999999488

# Material: Acciaio
Acciaio - Mass Density: 7850; Poisson Ratio: 0.3; Shear Modulus: 8000000000; Thermal Expansion Coefficient: 0.00001; Young Modulus: 20999999488

# Material: Acciaio
Acciaio - Mass Density: 7850; Poisson Ratio: 0.3; Shear Modulus: 8000000000; Thermal Expansion Coefficient: 0.00001; Young Modulus: 20999999488

# Material: Acciaio
Acciaio - Mass Density: 7850; Poisson Ratio: 0.3; Shear Modulus: 8000000000; Thermal Expansion Coefficient: 0.00001; Young Modulus: 20999999488

# Material: Acciaio
Acciaio - Mass Density: 7850; Poisson Ratio: 0.3; Shear Modulus: 8000000000; Thermal Expansion Coefficient: 0.00001; Young Modulus: 20999999488

# Material: Acciaio
Acciaio - Mass Density: 7850; Poisson Ratio: 0.3; Shear Modulus: 8000000000; Thermal Expansion Coefficient: 0.00001; Young Modulus: 20999999488

# Material: Acciaio
Acciaio - Mass Density: 7850; Poisson Ratio: 0.3; Shear Modulus: 8000000000; Thermal Expansion Coefficient: 0.00001; Young Modulus: 20999999488

# Material: Acciaio
Acciaio - Mass Density: 7850; Poisson Ratio: 0.3; Shear Modulus: 8000000000; Thermal Expansion Coefficient: 0.00001; Young Modulus: 20999999488

# Material: Acciaio
Acciaio - Mass Density: 7850; Poisson Ratio: 0.3; Shear Modulus: 8000000000; Thermal Expansion Coefficient: 0.00001; Young Modulus: 20999999488

# Material: Acciaio
Acciaio - Mass Density: 7850; Poisson Ratio: 0.3; Shear Modulus: 8000000000; Thermal Expansion Coefficient: 0.00001; Young Modulus: 20999999488

# Material: Acciaio
Acciaio - Mass Density: 7850; Poisson Ratio: 0.3; Shear Modulus: 8000000000; Thermal Expansion Coefficient: 0.00001; Young Modulus: 20999999488

# Material: Acciaio
Acciaio - Mass Density: 7850; Poisson Ratio: 0.3; Shear Modulus: 8000000000; Thermal Expansion Coefficient: 0.00001; Young Modulus: 20999999488

# Material: Acciaio
Acciaio - Mass Density: 7850; Poisson Ratio: 0.3; Shear Modulus: 8000000000; Thermal Expansion Coefficient: 0.00001; Young Modulus: 20999999488

# Material: Acciaio
Acciaio - Mass Density: 7850; Poisson Ratio: 0.3; Shear Modulus: 8000000000; Thermal Expansion Coefficient: 0.00001; Young Modulus: 20999999488

# Material: Acciaio
Acciaio - Mass Density: 7850; Poisson Ratio: 0.3; Shear Modulus: 8000000000; Thermal Expansion Coefficient: 0.00001; Young Modulus: 20999999488

# Material: Acciaio
Acciaio - Mass Density: 7850; Poisson Ratio: 0.3; Shear Modulus: 8000000000; Thermal Expansion Coefficient: 0.00001; Young Modulus: 20999999488

# Material: Acciaio
Acciaio - Mass Density: 7850; Poisson Ratio: 0.3; Shear Modulus: 8000000000; Thermal Expansion Coefficient: 0.00001; Young Modulus: 20999999488

# Material: Acciaio
Acciaio - Mass Density: 7850; Poisson Ratio: 0.3; Shear Modulus: 8000000000; Thermal Expansion Coefficient: 0.00001; Young Modulus: 20999999488

# Material: Acciaio
Acciaio - Mass Density: 7850; Poisson Ratio: 0.3; Shear Modulus: 8000000000; Thermal Expansion Coefficient: 0.00001; Young Modulus: 20999999488

# Material: Acciaio
Acciaio - Mass Density: 7850; Poisson Ratio: 0.3; Shear Modulus: 8000000000; Thermal Expansion Coefficient: 0.00001; Young Modulus: 20999999488

# Material: Acciaio
Acciaio - Mass Density: 7850; Poisson Ratio: 0.3; Shear Modulus: 8000000000; Thermal Expansion Coefficient: 0.00001; Young Modulus: 20999999488

# Material: Acciaio
Acciaio - Mass Density: 7850; Poisson Ratio: 0.3; Shear Modulus: 8000000000; Thermal Expansion Coefficient: 0.00001; Young Modulus: 20999999488

# Material: Acciaio
Acciaio - Mass Density: 7850; Poisson Ratio: 0.3; Shear Modulus: 8000000000; Thermal Expansion Coefficient: 0.00001; Young Modulus: 20999999488

# Material: Acciaio
Acciaio - Mass Density: 7850; Poisson Ratio: 0.3; Shear Modulus: 8000000000; Thermal Expansion Coefficient: 0.00001; Young Modulus: 20999999488

# Material: Acciaio
Acciaio - Mass Density: 7850; Poisson Ratio: 0.3; Shear Modulus: 8000000000; Thermal Expansion Coefficient: 0.00001; Young Modulus: 20999999488

# Material: Acciaio
Acciaio - Mass Density: 7850; Poisson Ratio: 0.3; Shear Modulus: 8000000000; Thermal Expansion Coefficient: 0.00001; Young Modulus: 20999999488

# Material: Acciaio
Acciaio - Mass Density: 7850; Poisson Ratio: 0.3; Shear Modulus: 8000000000; Thermal Expansion Coefficient: 0.00001; Young Modulus: 20999999488

# Material: Acciaio
Acciaio - Mass Density: 7850; Poisson Ratio: 0.3; Shear Modulus: 8000000000; Thermal Expansion Coefficient: 0.00001; Young Modulus: 20999999488

# Material: Acciaio
Acciaio - Mass Density: 7850; Poisson Ratio: 0.3; Shear Modulus: 8000000000; Thermal Expansion Coefficient: 0.00001; Young Modulus: 20999999488

# Material: Acciaio
Acciaio - Mass Density: 7850; Poisson Ratio: 0.3; Shear Modulus: 8000000000; Thermal Expansion Coefficient: 0.00001; Young Modulus: 20999999488

# Material: Acciaio
Acciaio - Mass Density: 7850; Poisson Ratio: 0.3; Shear Modulus: 8000000000; Thermal Expansion Coefficient: 0.00001; Young Modulus: 20999999488

# Material: Acciaio
Acciaio - Mass Density: 7850; Poisson Ratio: 0.3; Shear Modulus: 8000000000; Thermal Expansion Coefficient: 0.00001; Young Modulus: 20999999488

# Material: Acciaio
Acciaio - Mass Density: 7850; Poisson Ratio: 0.3; Shear Modulus: 8000000000; Thermal Expansion Coefficient: 0.00001; Young Modulus: 20999999488

# Material: Acciaio
Acciaio - Mass Density: 7850; Poisson Ratio: 0.3; Shear Modulus: 8000000000; Thermal Expansion Coefficient: 0.00001; Young Modulus: 20999999488

# Material: Acciaio
Acciaio - Mass Density: 7850; Poisson Ratio: 0.3; Shear Modulus: 8000000000; Thermal Expansion Coefficient: 0.00001; Young Modulus: 20999999488

# Material: Acciaio
Acciaio - Mass Density: 7850; Poisson Ratio: 0.3; Shear Modulus: 8000000000; Thermal Expansion Coefficient: 0.00001; Young Modulus: 20999999488

# Material: Acciaio
Acciaio - Mass Density: 7850; Poisson Ratio: 0.3; Shear Modulus: 8000000000; Thermal Expansion Coefficient: 0.00001; Young Modulus: 20999999488

# Material: Acciaio
Acciaio - Mass Density: 7850; Poisson Ratio: 0.3; Shear Modulus: 8000000000; Thermal Expansion Coefficient: 0.00001; Young Modulus: 20999999488

# Material: Acciaio
Acciaio - Mass Density: 7850; Poisson Ratio: 0.3; Shear Modulus: 8000000000; Thermal Expansion Coefficient: 0.00001; Young Modulus: 20999999488

# Material: Acciaio
Acciaio - Mass Density: 7850; Poisson Ratio: 0.3; Shear Modulus: 8000000000; Thermal Expansion Coefficient: 0.00001; Young Modulus: 20999999488

# Material: Acciaio
Acciaio - Mass Density: 7850; Poisson Ratio: 0.3; Shear Modulus: 8000000000; Thermal Expansion Coefficient: 0.00001; Young Modulus: 20999999488

# Material: Acciaio
Acciaio - Mass Density: 7850; Poisson Ratio: 0.3; Shear Modulus: 8000000000; Thermal Expansion Coefficient: 0.00001; Young Modulus: 20999999488

# Material: Acciaio
Acciaio - Mass Density: 7850; Poisson Ratio: 0.3; Shear Modulus: 8000000000; Thermal Expansion Coefficient: 0.00001; Young Modulus: 20999999488

# Material: Acciaio
Acciaio - Mass Density: 7850; Poisson Ratio: 0.3; Shear Modulus: 8000000000; Thermal Expansion Coefficient: 0.00001; Young Modulus: 20999999488

# Material: Acciaio
Acciaio - Mass Density: 7850; Poisson Ratio: 0.3; Shear Modulus: 8000000000; Thermal Expansion Coefficient: 0.00001; Young Modulus: 20999999488

# Material: Acciaio
Acciaio - Mass Density: 7850; Poisson Ratio: 0.3; Shear Modulus: 8000000000; Thermal Expansion Coefficient: 0.00001; Young Modulus: 20999999488

# Material: Acciaio
Acciaio - Mass Density: 7850; Poisson Ratio: 0.3; Shear Modulus: 8000000000; Thermal Expansion Coefficient: 0.00001; Young Modulus: 20999999488

# Material: Acciaio
Acciaio - Mass Density: 7850; Poisson Ratio: 0.3; Shear Modulus: 8000000000; Thermal Expansion Coefficient: 0.00001; Young Modulus: 20999999488

# Material: Acciaio
Acciaio - Mass Density: 7850; Poisson Ratio: 0.3; Shear Modulus: 8000000000; Thermal Expansion Coefficient: 0.00001; Young Modulus: 20999999488

# Material: Acciaio
Acciaio - Mass Density: 7850; Poisson Ratio: 0.3; Shear Modulus: 8000000000; Thermal Expansion Coefficient: 0.00001; Young Modulus: 20999999488

# Material: Acciaio
Acciaio - Mass Density: 7850; Poisson Ratio: 0.3; Shear Modulus: 8000000000; Thermal Expansion Coefficient: 0.00001; Young Modulus: 20999999488

# Material: Acciaio
Acciaio - Mass Density: 7850; Poisson Ratio: 0.3; Shear Modulus: 8000000000; Thermal Expansion Coefficient: 0.00001; Young Modulus: 20999999488

# Material: Acciaio
Acciaio - Mass Density: 7850; Poisson Ratio: 0.3; Shear Modulus: 8000000000; Thermal Expansion Coefficient: 0.00001; Young Modulus: 20999999488

# Material: Acciaio
Acciaio - Mass Density: 7850; Poisson Ratio: 0.3; Shear Modulus: 8000000000; Thermal Expansion Coefficient: 0.00001; Young Modulus: 20999999488

# Material: Acciaio
Acciaio - Mass Density: 7850; Poisson Ratio: 0.3; Shear Modulus: 8000000000; Thermal Expansion Coefficient: 0.00001; Young Modulus: 20999999488

# Material: Acciaio
Acciaio - Mass Density: 7850; Poisson Ratio: 0.3; Shear Modulus: 8000000000; Thermal Expansion Coefficient: 0.00001; Young Modulus: 20999999488

# Material: Acciaio
Acciaio - Mass Density: 7850; Poisson Ratio: 0.3; Shear Modulus: 8000000000; Thermal Expansion Coefficient: 0.00001; Young Modulus: 20999999488

# Material: Acciaio
Acciaio - Mass Density: 7850; Poisson Ratio: 0.3; Shear Modulus: 8000000000; Thermal Expansion Coefficient: 0.00001; Young Modulus: 20999999488

# Material: Acciaio
Acciaio - Mass Density: 7850; Poisson Ratio: 0.3; Shear Modulus: 8000000000; Thermal Expansion Coefficient: 0.00001; Young Modulus: 20999999488

# Material: Acciaio
Acciaio - Mass Density: 7850; Poisson Ratio: 0.3; Shear Modulus: 8000000000; Thermal Expansion Coefficient: 0.00001; Young Modulus: 20999999488

# Material: Acciaio
Acciaio - Mass Density: 7850; Poisson Ratio: 0.3; Shear Modulus: 8000000000; Thermal Expansion Coefficient: 0.00001; Young Modulus: 20999999488

# Material: Acciaio
Acciaio - Mass Density: 7850; Poisson Ratio: 0.3; Shear Modulus: 8000000000; Thermal Expansion Coefficient: 0.00001; Young Modulus: 20999999488

# Material: Acciaio
Acciaio - Mass Density: 7850; Poisson Ratio: 0.3; Shear Modulus: 8000000000; Thermal Expansion Coefficient: 0.00001; Young Modulus: 20999999488

# Material: Acciaio
Acciaio - Mass Density: 7850; Poisson Ratio: 0.3; Shear Modulus: 8000000000; Thermal Expansion Coefficient: 0.00001; Young Modulus: 20999999488

# Material: Acciaio
Acciaio - Mass Density: 7850; Poisson Ratio: 0.3; Shear Modulus: 8000000000; Thermal Expansion Coefficient: 0.00001; Young Modulus: 20999999488

# Material: Acciaio
Acciaio - Mass Density: 7850; Poisson Ratio: 0.3; Shear Modulus: 8000000000; Thermal Expansion Coefficient: 0.00001; Young Modulus: 20999999488

# Material: Acciaio
Acciaio - Mass Density: 7850; Poisson Ratio: 0.3; Shear Modulus: 8000000000; Thermal Expansion Coefficient: 0.00001; Young Modulus: 20999999488

# Material: Acciaio
Acciaio - Mass Density: 7850; Poisson Ratio: 0.3; Shear Modulus: 8000000000; Thermal Expansion Coefficient: 0.00001; Young Modulus: 20999999488

# Material: Acciaio
Acciaio - Mass Density: 7850; Poisson Ratio: 0.3; Shear Modulus: 8000000000; Thermal Expansion Coefficient: 0.00001; Young Modulus: 20999999488

# Material: Acciaio
Acciaio - Mass Density: 7850; Poisson Ratio: 0.3; Shear Modulus: 8000000000; Thermal Expansion Coefficient: 0.00001; Young Modulus: 20999999488

# Material: Acciaio
Acciaio - Mass Density: 7850; Poisson Ratio: 0.3; Shear Modulus: 8000000000; Thermal Expansion Coefficient: 0.00001; Young Modulus: 20999999488

# Material: Acciaio
Acciaio - Mass Density: 7850; Poisson Ratio: 0.3; Shear Modulus: 8000000000; Thermal Expansion Coefficient: 0.00001; Young Modulus: 20999999488

# Material: Acciaio
Acciaio - Mass Density: 7850; Poisson Ratio: 0.3; Shear Modulus: 8000000000; Thermal Expansion Coefficient: 0.00001; Young Modulus: 20999999488

# Material: Acciaio
Acciaio - Mass Density: 7850; Poisson Ratio: 0.3; Shear Modulus: 8000000000; Thermal Expansion Coefficient: 0.00001; Young Modulus: 20999999488

# Material: Acciaio
Acciaio - Mass Density: 7850; Poisson Ratio: 0.3; Shear Modulus: 8000000000; Thermal Expansion Coefficient: 0.00001; Young Modulus: 20999999488

# Material: Acciaio
Acciaio - Mass Density: 7850; Poisson Ratio: 0.3; Shear Modulus: 8000000000; Thermal Expansion Coefficient: 0.00001; Young Modulus: 20999999488

# Material: Acciaio
Acciaio - Mass Density: 7850; Poisson Ratio: 0.3; Shear Modulus: 8000000000; Thermal Expansion Coefficient: 0.00001; Young Modulus: 20999999488

# Material: Acciaio
Acciaio - Mass Density: 7850; Poisson Ratio: 0.3; Shear Modulus: 8000000000; Thermal Expansion Coefficient: 0.00001; Young Modulus: 20999999488

# Material: Acciaio
Acciaio - Mass Density: 7850; Poisson Ratio: 0.3; Shear Modulus: 8000000000; Thermal Expansion Coefficient: 0.00001; Young Modulus: 20999999488

# Material: Acciaio
Acciaio - Mass Density: 7850; Poisson Ratio: 0.3; Shear Modulus: 8000000000; Thermal Expansion Coefficient: 0.00001; Young Modulus: 20999999488

# Material: Acciaio
Acciaio - Mass Density: 7850; Poisson Ratio: 0.3; Shear Modulus: 8000000000; Thermal Expansion Coefficient: 0.00001; Young Modulus: 20999999488

# Material: Acciaio
Acciaio - Mass Density: 7850; Poisson Ratio: 0.3; Shear Modulus: 8000000000; Thermal Expansion Coefficient: 0.00001; Young Modulus: 20999999488

# Material: Acciaio
Acciaio - Mass Density: 7850; Poisson Ratio: 0.3; Shear Modulus: 8000000000; Thermal Expansion Coefficient: 0.00001; Young Modulus: 20999999488

# Material: Acciaio
Acciaio - Mass Density: 7850; Poisson Ratio: 0.3; Shear Modulus: 8000000000; Thermal Expansion Coefficient: 0.00001; Young Modulus: 20999999488

# Material: Acciaio
Acciaio - Mass Density: 7850; Poisson Ratio: 0.3; Shear Modulus: 8000000000; Thermal Expansion Coefficient: 0.00001; Young Modulus: 20999999488

# Material: Acciaio
Acciaio - Mass Density: 7850; Poisson Ratio: 0.3; Shear Modulus: 8000000000; Thermal Expansion Coefficient: 0.00001; Young Modulus: 20999999488

# Material: Acciaio
Acciaio - Mass Density: 7850; Poisson Ratio: 0.3; Shear Modulus: 8000000000; Thermal Expansion Coefficient: 0.00001; Young Modulus: 20999999488

# Material: Acciaio
Acciaio - Mass Density: 7850; Poisson Ratio: 0.3; Shear Modulus: 8000000000; Thermal Expansion Coefficient: 0.00001; Young Modulus: 20999999488

# Material: Acciaio
Acciaio - Mass Density: 7850; Poisson Ratio: 0.3; Shear Modulus: 8000000000; Thermal Expansion Coefficient: 0.00001; Young Modulus: 20999999488

# Material: Acciaio
Acciaio - Mass Density: 7850; Poisson Ratio: 0.3; Shear Modulus: 8000000000; Thermal Expansion Coefficient: 0.00001; Young Modulus: 20999999488

# Material: Acciaio
Acciaio - Mass Density: 7850; Poisson Ratio: 0.3; Shear Modulus: 8000000000; Thermal Expansion Coefficient: 0.00001; Young Modulus: 20999999488

# Material: Acciaio
Acciaio - Mass Density: 7850; Poisson Ratio: 0.3; Shear Modulus: 8000000000; Thermal Expansion Coefficient: 0.00001; Young Modulus: 20999999488

# Material: Acciaio
Acciaio - Mass Density: 7850; Poisson Ratio: 0.3; Shear Modulus: 8000000000; Thermal Expansion Coefficient: 0.00001; Young Modulus: 20999999488

# Material: Acciaio
Acciaio - Mass Density: 7850; Poisson Ratio: 0.3; Shear Modulus: 8000000000; Thermal Expansion Coefficient: 0.00001; Young Modulus: 20999999488

# Material: Acciaio
Acciaio - Mass Density: 7850; Poisson Ratio: 0.3; Shear Modulus: 8000000000; Thermal Expansion Coefficient: 0.00001; Young Modulus: 20999999488

# Material: Acciaio
Acciaio - Mass Density: 7850; Poisson Ratio: 0.3; Shear Modulus: 8000000000; Thermal Expansion Coefficient: 0.00001; Young Modulus: 20999999488

# Material: Acciaio
Acciaio - Mass Density: 7850; Poisson Ratio: 0.3; Shear Modulus: 8000000000; Thermal Expansion Coefficient: 0.00001; Young Modulus: 20999999488

# Material: Acciaio
Acciaio - Mass Density: 7850; Poisson Ratio: 0.3; Shear Modulus: 8000000000; Thermal Expansion Coefficient: 0.00001; Young Modulus: 20999999488

# Material: Acciaio
Acciaio - Mass Density: 7850; Poisson Ratio: 0.3; Shear Modulus: 8000000000; Thermal Expansion Coefficient: 0.00001; Young Modulus: 20999999488

# Material: Acciaio
Acciaio - Mass Density: 7850; Poisson Ratio: 0.3; Shear Modulus: 8000000000; Thermal Expansion Coefficient: 0.00001; Young Modulus: 20999999488

# Material: Acciaio
Acciaio - Mass Density: 7850; Poisson Ratio: 0.3; Shear Modulus: 8000000000; Thermal Expansion Coefficient: 0.00001; Young Modulus: 20999999488

# Material: Acciaio
Acciaio - Mass Density: 7850; Poisson Ratio: 0.3; Shear Modulus: 8000000000; Thermal Expansion Coefficient: 0.00001; Young Modulus: 20999999488

# Material: Acciaio
Acciaio - Mass Density: 7850; Poisson Ratio: 0.3; Shear Modulus: 8000000000; Thermal Expansion Coefficient: 0.00001; Young Modulus: 20999999488

# Material: Acciaio
Acciaio - Mass Density: 7850; Poisson Ratio: 0.3; Shear Modulus: 8000000000; Thermal Expansion Coefficient: 0.00001; Young Modulus: 20999999488

# Material: Acciaio
Acciaio - Mass Density: 7850; Poisson Ratio: 0.3; Shear Modulus: 8000000000; Thermal Expansion Coefficient: 0.00001; Young Modulus: 20999999488

# Material: Acciaio
Acciaio - Mass Density: 7850; Poisson Ratio: 0.3; Shear Modulus: 8000000000; Thermal Expansion Coefficient: 0.00001; Young Modulus: 20999999488

# Material: Acciaio
Acciaio - Mass Density: 7850; Poisson Ratio: 0.3; Shear Modulus: 8000000000; Thermal Expansion Coefficient: 0.00001; Young Modulus: 20999999488

# Material: Acciaio
Acciaio - Mass Density: 7850; Poisson Ratio: 0.3; Shear Modulus: 8000000000; Thermal Expansion Coefficient: 0.00001; Young Modulus: 20999999488

# Material: Acciaio
Acciaio - Mass Density: 7850; Poisson Ratio: 0.3; Shear Modulus: 8000000000; Thermal Expansion Coefficient: 0.00001; Young Modulus: 20999999488

# Material: Acciaio
Acciaio - Mass Density: 7850; Poisson Ratio: 0.3; Shear Modulus: 8000000000; Thermal Expansion Coefficient: 0.00001; Young Modulus: 20999999488

# Material: Acciaio
Acciaio - Mass Density: 7850; Poisson Ratio: 0.3; Shear Modulus: 8000000000; Thermal Expansion Coefficient: 0.00001; Young Modulus: 20999999488

# Material: Acciaio
Acciaio - Mass Density: 7850; Poisson Ratio: 0.3; Shear Modulus: 8000000000; Thermal Expansion Coefficient: 0.00001; Young Modulus: 20999999488

# Material: Acciaio
Acciaio - Mass Density: 7850; Poisson Ratio: 0.3; Shear Modulus: 8000000000; Thermal Expansion Coefficient: 0.00001; Young Modulus: 20999999488

# Material: Acciaio
Acciaio - Mass Density: 7850; Poisson Ratio: 0.3; Shear Modulus: 8000000000; Thermal Expansion Coefficient: 0.00001; Young Modulus: 20999999488

# Material: Acciaio
